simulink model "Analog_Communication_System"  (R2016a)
settings: Solver=ode3  StartTime=0.0  StopTime=6  FixedStep=1/5000000  RelTol=1e-3
libraries: dsparch4 x4, commchan3 x2

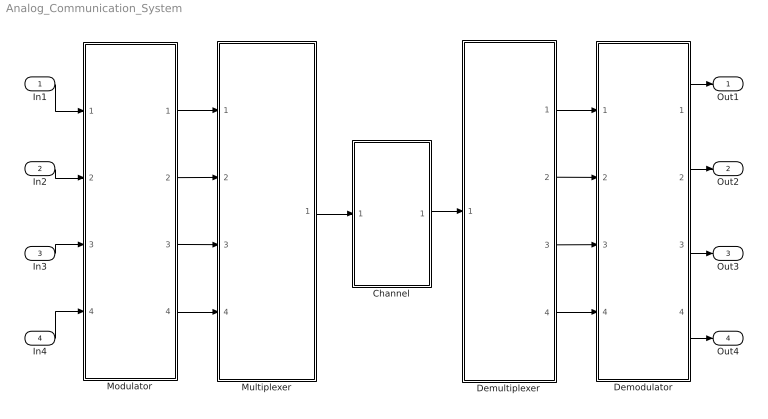
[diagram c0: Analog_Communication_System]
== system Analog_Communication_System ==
  In1 : Inport
  In2 : Inport  Port=2
  In3 : Inport  Port=3
  In4 : Inport  Port=4
  Channel : Subsystem
  Demodulator : Subsystem
  Demultiplexer : Subsystem
  Modulator : Subsystem
  Multiplexer : Subsystem
  Out1 : Outport
  Out2 : Outport  Port=2
  Out3 : Outport  Port=3
  Out4 : Outport  Port=4
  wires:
  In1/1 -> Modulator/1(In1)
  In2/1 -> Modulator/2(In2)
  In3/1 -> Modulator/3(In3)
  In4/1 -> Modulator/4(In4)
  Modulator/1(Out1) -> Multiplexer/1(In1)
  Modulator/2(Out2) -> Multiplexer/2(In2)
  Modulator/3(Out3) -> Multiplexer/3(In3)
  Modulator/4(Out4) -> Multiplexer/4(In4)
  Multiplexer/1(Out1) -> Channel/1(In1)
  Channel/1(Out1) -> Demultiplexer/1(In1)
  Demultiplexer/1(Out1) -> Demodulator/1(In1)
  Demultiplexer/2(Out2) -> Demodulator/2(In2)
  Demultiplexer/3(Out3) -> Demodulator/3(In3)
  Demultiplexer/4(Out4) -> Demodulator/4(In4)
  Demodulator/1(Out1) -> Out1/1
  Demodulator/2(Out2) -> Out2/1
  Demodulator/3(Out3) -> Out3/1
  Demodulator/4(Out4) -> Out4/1

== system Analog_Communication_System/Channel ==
  In1 : Inport
  AWGN Channel : commchan3/AWGN Channel  InputProcessing=Columns as channels (frame based)  seed=67  noiseMode="Signal to noise ratio  (Eb/No)"  EbNodB=10  EsNodB=10  SNRdB=10  bitsPerSym=2  Ps=1  Tsym=1/5000000  variance=1
  Releigh Channel : Subsystem
  Out1 : Outport
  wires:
  AWGN Channel/1 -> Releigh Channel/1(In1)
  In1/1 -> AWGN Channel/1
  Releigh Channel/1(Out1) -> Out1/1

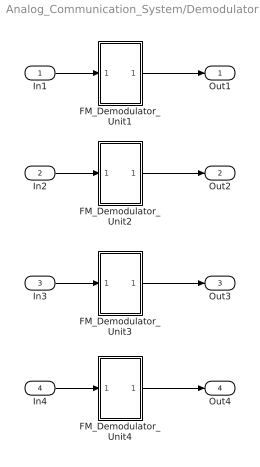
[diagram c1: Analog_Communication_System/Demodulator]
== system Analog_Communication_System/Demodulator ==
  In1 : Inport
  In2 : Inport  Port=2
  In3 : Inport  Port=3
  In4 : Inport  Port=4
  FM_Demodulator_Unit1 : Subsystem
  FM_Demodulator_Unit2 : Subsystem
  FM_Demodulator_Unit3 : Subsystem
  FM_Demodulator_Unit4 : Subsystem
  Out1 : Outport
  Out2 : Outport  Port=2
  Out3 : Outport  Port=3
  Out4 : Outport  Port=4
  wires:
  FM_Demodulator_Unit3/1(Out1) -> Out3/1
  FM_Demodulator_Unit2/1(Out1) -> Out2/1
  FM_Demodulator_Unit4/1(Out1) -> Out4/1
  In1/1 -> FM_Demodulator_Unit1/1(In1)
  In4/1 -> FM_Demodulator_Unit4/1(In1)
  FM_Demodulator_Unit1/1(Out1) -> Out1/1
  In2/1 -> FM_Demodulator_Unit2/1(In1)
  In3/1 -> FM_Demodulator_Unit3/1(In1)

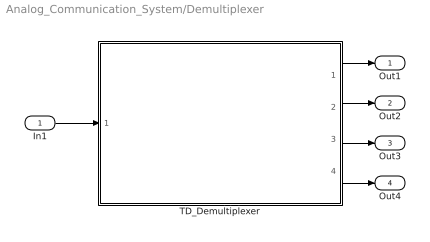
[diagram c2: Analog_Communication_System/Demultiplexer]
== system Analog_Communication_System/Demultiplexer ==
  In1 : Inport
  TD_Demultiplexer : MATLAB Function  TreatAsAtomicUnit=on
  Out1 : Outport
  Out2 : Outport  Port=2
  Out3 : Outport  Port=3
  Out4 : Outport  Port=4
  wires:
  TD_Demultiplexer/4(S4) -> Out4/1
  TD_Demultiplexer/1(S1) -> Out1/1
  In1/1 -> TD_Demultiplexer/1(Y)
  TD_Demultiplexer/2(S2) -> Out2/1
  TD_Demultiplexer/3(S3) -> Out3/1

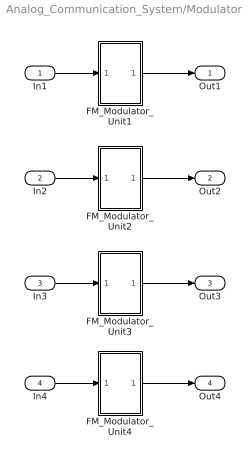
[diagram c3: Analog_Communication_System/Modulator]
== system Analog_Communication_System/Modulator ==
  In1 : Inport
  In2 : Inport  Port=2
  In3 : Inport  Port=3
  In4 : Inport  Port=4
  FM_Modulator_Unit1 : Subsystem
  FM_Modulator_Unit2 : Subsystem
  FM_Modulator_Unit3 : Subsystem
  FM_Modulator_Unit4 : Subsystem
  Out1 : Outport
  Out2 : Outport  Port=2
  Out3 : Outport  Port=3
  Out4 : Outport  Port=4
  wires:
  In1/1 -> FM_Modulator_Unit1/1(In1)
  FM_Modulator_Unit1/1(Out1) -> Out1/1
  In2/1 -> FM_Modulator_Unit2/1(In1)
  FM_Modulator_Unit2/1(Out1) -> Out2/1
  In3/1 -> FM_Modulator_Unit3/1(In1)
  FM_Modulator_Unit3/1(Out1) -> Out3/1
  In4/1 -> FM_Modulator_Unit4/1(In1)
  FM_Modulator_Unit4/1(Out1) -> Out4/1

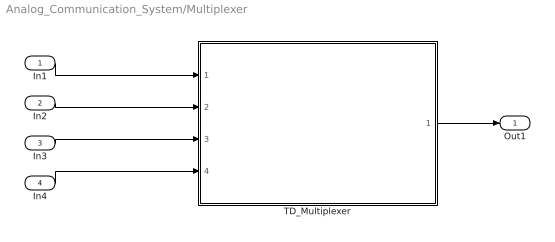
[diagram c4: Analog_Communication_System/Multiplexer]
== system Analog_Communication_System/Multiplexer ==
  In1 : Inport
  In2 : Inport  Port=2
  In3 : Inport  Port=3
  In4 : Inport  Port=4
  TD_Multiplexer : MATLAB Function  TreatAsAtomicUnit=on
  Out1 : Outport
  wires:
  In2/1 -> TD_Multiplexer/2(S2)
  In4/1 -> TD_Multiplexer/4(S4)
  In1/1 -> TD_Multiplexer/1(S1)
  In3/1 -> TD_Multiplexer/3(S3)
  TD_Multiplexer/1(MIXSOUT) -> Out1/1

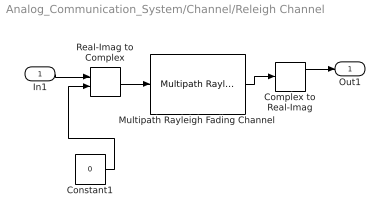
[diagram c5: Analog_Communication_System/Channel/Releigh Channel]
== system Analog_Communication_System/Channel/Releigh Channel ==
  In1 : Inport
  Complex to Real-Imag : ComplexToRealImag
  Constant1 : Constant  Value=0  SampleTime=1/5000000
  Multipath Rayleigh Fading Channel : commchan3/Multipath Rayleigh Fading Channel  maxDopplerShift=1  spectrumType=Jakes  sigmaGaussian=1/sqrt(2)  coeffRounded=[1 -1.72 0.785]  freqMinMaxRJakes=[0 1]  freqMinMaxAJakes=[0 1]  sigmaGaussian1=1/sqrt(2)  sigmaGaussian2=1/sqrt(2)  centerFreqGaussian1=0.0  centerFreqGaussian2=0.0  gainGaussian1=0.5  gainGaussian2=0.5  coeffBell=9  dopplerSpectrum=doppler.jakes  pathDelays=0  avgPathGaindB=-3  normalizePathGains=on  seed=73  enableProbe=0  openVisAtStart=off  outPathGains=off  outDelay=off
  Real-Imag to Complex : RealImagToComplex
  Out1 : Outport
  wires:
  Real-Imag to Complex/1 -> Multipath Rayleigh Fading Channel/1
  Multipath Rayleigh Fading Channel/1 -> Complex to Real-Imag/1
  Constant1/1 -> Real-Imag to Complex/2
  Complex to Real-Imag/1 -> Out1/1
  Complex to Real-Imag/2 -> ?
  In1/1 -> Real-Imag to Complex/1

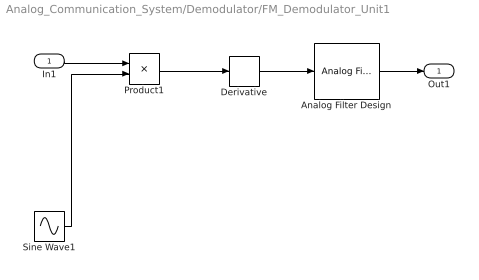
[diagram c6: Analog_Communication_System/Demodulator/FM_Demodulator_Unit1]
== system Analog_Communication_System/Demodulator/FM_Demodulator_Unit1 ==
  In1 : Inport
  Analog Filter Design : dsparch4/Analog Filter Design  method=Butterworth  filttype=Lowpass  N=10  Wlo=45000*2*pi  Whi=80  Rp=2  Rs=40
  Derivative : Derivative
  Product1 : Product
  Sine Wave1 : Sin  Frequency=500000*2*pi  Phase=-1.5*pi
  Out1 : Outport
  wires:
  Analog Filter Design/1 -> Out1/1
  Product1/1 -> Derivative/1
  Sine Wave1/1 -> Product1/2
  In1/1 -> Product1/1
  Derivative/1 -> Analog Filter Design/1

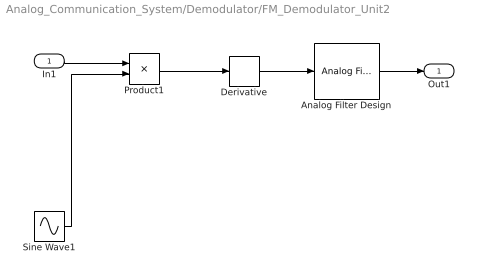
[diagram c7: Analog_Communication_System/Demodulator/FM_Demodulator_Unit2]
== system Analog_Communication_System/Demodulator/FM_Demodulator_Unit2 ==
  In1 : Inport
  Analog Filter Design : dsparch4/Analog Filter Design  method=Butterworth  filttype=Lowpass  N=10  Wlo=45000*2*pi  Whi=80  Rp=2  Rs=40
  Derivative : Derivative
  Product1 : Product
  Sine Wave1 : Sin  Frequency=500000*2*pi  Phase=-1.5*pi
  Out1 : Outport
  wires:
  Analog Filter Design/1 -> Out1/1
  Product1/1 -> Derivative/1
  Sine Wave1/1 -> Product1/2
  In1/1 -> Product1/1
  Derivative/1 -> Analog Filter Design/1

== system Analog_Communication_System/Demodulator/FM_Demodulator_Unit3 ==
  In1 : Inport
  Analog Filter Design : dsparch4/Analog Filter Design  method=Butterworth  filttype=Lowpass  N=10  Wlo=45000*2*pi  Whi=80  Rp=2  Rs=40
  Derivative : Derivative
  Product1 : Product
  Sine Wave1 : Sin  Frequency=500000*2*pi  Phase=-1.5*pi
  Out1 : Outport
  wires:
  Analog Filter Design/1 -> Out1/1
  Product1/1 -> Derivative/1
  Sine Wave1/1 -> Product1/2
  In1/1 -> Product1/1
  Derivative/1 -> Analog Filter Design/1

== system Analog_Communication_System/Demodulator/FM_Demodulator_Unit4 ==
  In1 : Inport
  Analog Filter Design : dsparch4/Analog Filter Design  method=Butterworth  filttype=Lowpass  N=10  Wlo=45000*2*pi  Whi=80  Rp=2  Rs=40
  Derivative : Derivative
  Product1 : Product
  Sine Wave1 : Sin  Frequency=500000*2*pi  Phase=-1.5*pi
  Out1 : Outport
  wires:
  Analog Filter Design/1 -> Out1/1
  Product1/1 -> Derivative/1
  Sine Wave1/1 -> Product1/2
  In1/1 -> Product1/1
  Derivative/1 -> Analog Filter Design/1

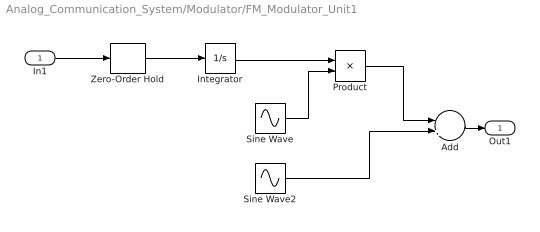
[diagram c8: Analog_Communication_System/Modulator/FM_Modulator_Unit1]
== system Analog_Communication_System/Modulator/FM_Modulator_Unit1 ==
  In1 : Inport
  Add : Sum  Inputs=-+
  Integrator : Integrator
  Product : Product
  Sine Wave : Sin  Frequency=500000*2*pi  Phase=-0.5*pi
  Sine Wave2 : Sin  Frequency=500000*2*pi
  Zero-Order Hold : ZeroOrderHold  SampleTime=0.000005
  Out1 : Outport
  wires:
  Zero-Order Hold/1 -> Integrator/1
  In1/1 -> Zero-Order Hold/1
  Sine Wave/1 -> Product/2
  Sine Wave2/1 -> Add/2
  Product/1 -> Add/1
  Integrator/1 -> Product/1
  Add/1 -> Out1/1

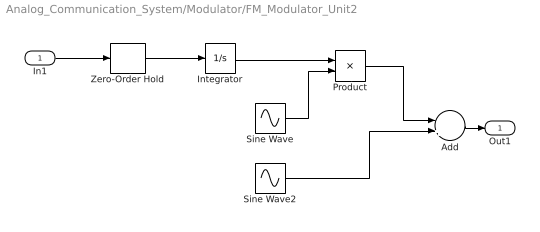
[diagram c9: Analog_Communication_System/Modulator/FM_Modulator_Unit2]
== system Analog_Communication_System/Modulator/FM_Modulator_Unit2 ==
  In1 : Inport
  Add : Sum  Inputs=-+
  Integrator : Integrator
  Product : Product
  Sine Wave : Sin  Frequency=500000*2*pi  Phase=-0.5*pi
  Sine Wave2 : Sin  Frequency=500000*2*pi
  Zero-Order Hold : ZeroOrderHold  SampleTime=0.000005
  Out1 : Outport
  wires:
  Zero-Order Hold/1 -> Integrator/1
  In1/1 -> Zero-Order Hold/1
  Sine Wave/1 -> Product/2
  Sine Wave2/1 -> Add/2
  Product/1 -> Add/1
  Integrator/1 -> Product/1
  Add/1 -> Out1/1

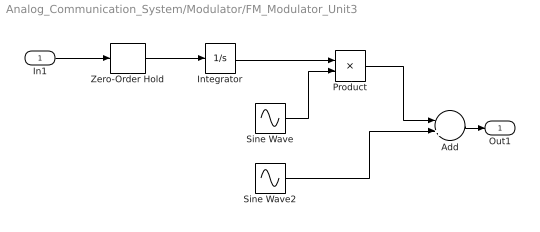
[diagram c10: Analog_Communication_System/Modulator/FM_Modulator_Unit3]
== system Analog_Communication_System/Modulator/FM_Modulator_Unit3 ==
  In1 : Inport
  Add : Sum  Inputs=-+
  Integrator : Integrator
  Product : Product
  Sine Wave : Sin  Frequency=500000*2*pi  Phase=-0.5*pi
  Sine Wave2 : Sin  Frequency=500000*2*pi
  Zero-Order Hold : ZeroOrderHold  SampleTime=0.000005
  Out1 : Outport
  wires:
  Zero-Order Hold/1 -> Integrator/1
  In1/1 -> Zero-Order Hold/1
  Sine Wave/1 -> Product/2
  Sine Wave2/1 -> Add/2
  Product/1 -> Add/1
  Integrator/1 -> Product/1
  Add/1 -> Out1/1

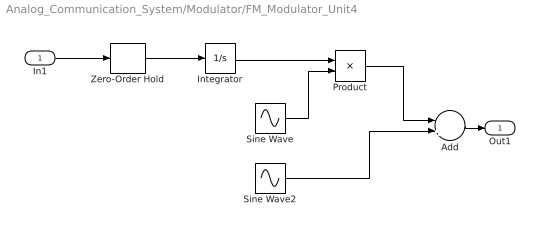
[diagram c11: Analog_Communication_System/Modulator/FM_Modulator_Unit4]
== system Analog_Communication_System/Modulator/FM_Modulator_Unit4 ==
  In1 : Inport
  Add : Sum  Inputs=-+
  Integrator : Integrator
  Product : Product
  Sine Wave : Sin  Frequency=500000*2*pi  Phase=-0.5*pi
  Sine Wave2 : Sin  Frequency=500000*2*pi
  Zero-Order Hold : ZeroOrderHold  SampleTime=0.000005
  Out1 : Outport
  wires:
  Zero-Order Hold/1 -> Integrator/1
  In1/1 -> Zero-Order Hold/1
  Sine Wave/1 -> Product/2
  Sine Wave2/1 -> Add/2
  Product/1 -> Add/1
  Integrator/1 -> Product/1
  Add/1 -> Out1/1

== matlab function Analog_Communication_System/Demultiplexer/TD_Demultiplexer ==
function [S1,S2,S3,S4] = TD_Demultiplexer(Y)
tm=1 ;
t=1;
dt=1;
S1=zeros(1,length(Y)/4);
S2=zeros(1,length(Y)/4);
S3=zeros(1,length(Y)/4);
S4=zeros(1,length(Y)/4);
while tm<=length(Y)
for i=1:4
    if i==1
        S1(t)=Y(tm);
        tm=tm+dt;
    end
    if i==2   
     S2(t)=Y(tm);
        tm=tm+dt;
    end
     if i==3  
     S3(t)=Y(tm);
        tm=tm+dt;
      end
     if i==4 
     S4(t)=Y(tm);
        tm=tm+dt;
        t=t+dt;
    end
end
end

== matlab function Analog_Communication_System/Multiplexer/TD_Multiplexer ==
function  MIXSOUT= TD_Multiplexer(S1,S2,S3,S4)
dt=1;
t=length(S1);
tm=1;
tmx=1;
MIXSOUT=zeros(1,4*t);
while tmx<=4*t
    for i=1:4
    %可能有问题信号长度不同
    if i==1
       MIXSOUT(tmx)=S1(tm);
       tmx=tmx+dt;
    end 
    if i==2
    MIXSOUT(tmx)=S2(tm);
    tmx=tmx+dt;
    end
    if i==3
    MIXSOUT(tmx)=S3(tm);
    tmx=tmx+dt;
    end 
    if i==4
    MIXSOUT(tmx)=S4(tm);
    tmx=tmx+dt;
    tm=tm+dt;
    end
    end
end
